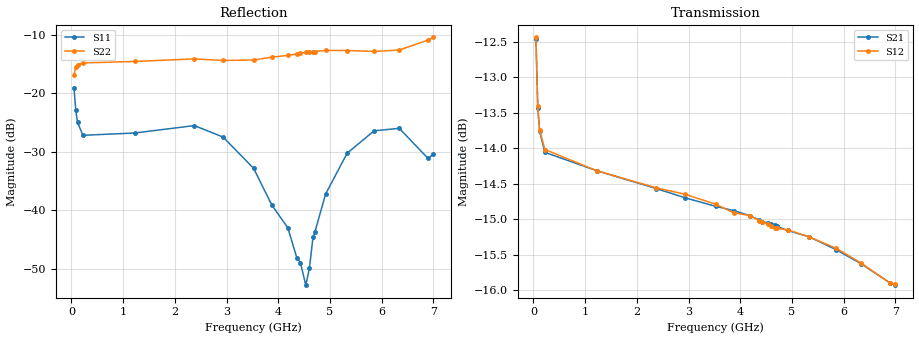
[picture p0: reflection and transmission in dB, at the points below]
! Integrated Device Technology
! Corporate Headquarters
! 6024 Silver Creek Valley Road
! San Jose, CA 95138  USA
! Phone:  1-408-284-8200
! Toll Free:  1-800-223-1366
! Webpage:  http://www.idt.com/
! Timing and RF Division
! 515 Groton Road, Suite 102
! Westford, MA 01886-6024
! Device:  F2258
! Description: Voltage Variable RF Attenuator
! Frequency:  50.0 -  6000.00 MHz
! Package:  3x3 mm Thin QFN Plastic Package: 16 pin
! Ports:  2 RF, 2 DC
!  Pin  1  = NC
!  Pin  2  = NC
!  Pin  3  = RF2  = Port 2
!  Pin  4  = GND
!  Pin  5  = Vdd
!  Pin  6  = NC
!  Pin  7  = VCTRL
!  Pin  8  = NC
!  Pin  9  = GND
!  Pin 10  = RF1  = Port 1
!  Pin 11  = NC
!  Pin 12  = NC
!  Pin 13  = NC
!  Pin 14  = NC
!  Pin 15  = NC
!  Pin 16  = NC
! Vcntrl:  1.150 Volts
! Vdd:  +3.300 Volts
! Current:  1.164 mA
! Data:  The device was measured on a the F2258 evaluation board which has
!  individual transmission lines to the RF pins.  Data was collected
!  using a calibrated network analyzer.  The evaluation board was
!  de-embedded using a TRL calibration technique.
!  The reference plane is the edge of the package pin.
! Misc:  SN 10
!  Action Tracker AT0285
! Date Measured:  2014-12-10
! Date:  2016-01-13  MJV
! Note:
!  Integrated Device Technology supplies this data as a sample of measured
!  data at the package pin for this product.  Your particular data for this
!  product may vary.
!  Data was taken at 25 degrees C.
!  Integrated Device Technology reserves the right to change this data at anytime.
!Freq_(GHz)  S11M_(dB)  S11P_(deg)  S21M_(dB)  S21P_(deg)  S12M_(dB)  S12P_(deg)  S22M_(dB)  S22P_(deg)
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# GHz S dB R 50
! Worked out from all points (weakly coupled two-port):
!   201 points, 50 MHz to 7 GHz, reference 50 ohm
!   highest |S21| = -12.46 dB at 50 MHz (marker M1); lowest = -15.9 dB at 7 GHz (marker M2)
!   lowest |S11| = -52.8 dB at 4.533 GHz (marker M3), VSWR 1.00, Z = 50.2 + j0.0716 ohm
!   |S11| at or under -10 dB: start of sweep to end of sweep
!   |S22| runs from -16.9 to -10.4 dB; largest |S21 - S12| = 0.0011
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0.05  -19.03 -89.8  -12.46 -21.6  -12.44 -21.6  -16.88 -23.4
0.08475  -22.90 -71.9  -13.43 -15.4  -13.40 -15.4  -15.51 -12.8
0.1195  -24.98 -58.3  -13.76 -12.4  -13.74 -12.4  -15.11 -10.5
0.22375  -27.17 -36.1  -14.06 -9.6  -14.02 -9.6  -14.81 -9.9
1.2315  -26.77 -16.3  -14.32 -20.8  -14.32 -20.8  -14.56 -35.6
2.37825  -25.51 -4.9  -14.57 -37.6  -14.56 -37.6  -14.12 -63.5
2.93425  -27.47 4.3  -14.70 -46.0  -14.65 -46.0  -14.39 -79.9
3.525  -32.82 18.5  -14.82 -55.0  -14.79 -55.1  -14.31 -102.0
3.8725  -39.04 34.2  -14.88 -60.3  -14.91 -60.3  -13.83 -114.8
4.18525  -42.96 58.6  -14.95 -65.0  -14.95 -65.0  -13.52 -123.9
4.359  -48.07 53.5  -15.01 -67.7  -15.02 -67.6  -13.29 -128.7
4.4285  -48.91 45.1  -15.04 -68.7  -15.04 -68.7  -13.17 -130.2
4.53275  -52.75 18.0  -15.05 -70.2  -15.07 -70.2  -13.00 -132.3
4.60225  -49.91 2.4  -15.07 -71.2  -15.10 -71.1  -12.89 -133.6
4.67175  -44.61 -18.9  -15.08 -72.2  -15.13 -72.2  -12.88 -134.5
4.7065  -43.76 -22.0  -15.10 -72.7  -15.13 -72.7  -12.86 -135.4
4.915  -37.21 -32.0  -15.16 -75.8  -15.15 -75.8  -12.68 -138.6
5.332  -30.23 -25.3  -15.25 -81.8  -15.25 -81.8  -12.69 -144.6
5.85325  -26.41 -13.4  -15.43 -89.2  -15.41 -89.2  -12.85 -153.9
6.33975  -25.97 1.4  -15.63 -96.1  -15.62 -96.2  -12.61 -166.1
6.89575  -31.11 67.6  -15.90 -103.5  -15.90 -103.5  -10.91 178.3
7  -30.39 94.3  -15.93 -104.7  -15.92 -104.8  -10.45 175.7
